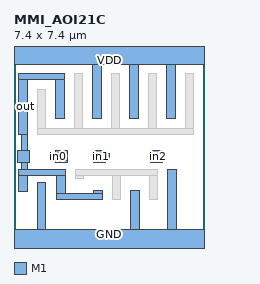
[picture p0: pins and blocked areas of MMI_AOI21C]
MACRO MMI_AOI21C
	CLASS CORE ;
	FOREIGN MMI_AOI21C 0 0 ;
	SIZE 7.4 BY 7.4 ;
	SYMMETRY X Y ;
	SITE CORE1 ;
	PIN out
		DIRECTION output ;
		USE SIGNAL ;
		PORT
			LAYER M1 ;
			RECT 0.18 6.34 1.96 6.57 ;
			LAYER M1 ;
			RECT 0.18 4.195 0.52 6.34 ;
			LAYER M1 ;
			RECT 1.62 4.815 1.96 6.34 ;
			LAYER M1 ;
			RECT 0.29 3.555 0.52 4.195 ;
			LAYER M1 ;
			RECT 0.145 3.105 0.595 3.555 ;
			LAYER M1 ;
			RECT 0.29 2.805 0.52 3.105 ;
			LAYER M1 ;
			RECT 0.18 2.575 2 2.805 ;
			LAYER M1 ;
			RECT 0.18 1.965 0.52 2.575 ;
			LAYER M1 ;
			RECT 1.66 1.89 2 2.575 ;
			LAYER M1 ;
			RECT 3.1 1.89 3.44 2 ;
			LAYER M1 ;
			RECT 1.66 1.66 3.44 1.89 ;
		END
		AntennaDiffArea 4.2872 ;
	END out
	PIN in1
		DIRECTION input ;
		USE SIGNAL ;
		PORT
			LAYER M1 ;
			RECT 3.105 3.5 3.555 3.555 ;
			LAYER M1 ;
			RECT 3.105 3.445 3.64 3.5 ;
			LAYER M1 ;
			RECT 3.105 3.215 3.705 3.445 ;
			LAYER M1 ;
			RECT 3.105 3.16 3.64 3.215 ;
			LAYER M1 ;
			RECT 3.105 3.105 3.555 3.16 ;
		END
		AntennaGateArea 1.9872 ;
	END in1
	PIN GND
		DIRECTION inout ;
		USE GROUND ;
		PORT
			LAYER M1 ;
			RECT 0.9 0.5 1.24 2.305 ;
			LAYER M1 ;
			RECT 4.54 0.5 4.88 2 ;
			LAYER M1 ;
			RECT 5.98 0.5 6.32 2.805 ;
			LAYER M1 ;
			RECT 0 -0.5 7.4 0.5 ;
		END
	END GND
	PIN in2
		DIRECTION input ;
		USE SIGNAL ;
		PORT
			LAYER M1 ;
			RECT 5.325 3.5 5.775 3.555 ;
			LAYER M1 ;
			RECT 5.325 3.445 5.8 3.5 ;
			LAYER M1 ;
			RECT 5.325 3.215 5.865 3.445 ;
			LAYER M1 ;
			RECT 5.325 3.16 5.8 3.215 ;
			LAYER M1 ;
			RECT 5.325 3.105 5.775 3.16 ;
		END
		AntennaGateArea 1.9872 ;
	END in2
	PIN VDD
		DIRECTION inout ;
		USE POWER ;
		PORT
			LAYER M1 ;
			RECT 0 6.9 7.4 7.9 ;
			LAYER M1 ;
			RECT 3.06 4.815 3.4 6.9 ;
			LAYER M1 ;
			RECT 4.5 4.815 4.84 6.9 ;
			LAYER M1 ;
			RECT 5.94 4.815 6.28 6.9 ;
		END
	END VDD
	PIN in0
		DIRECTION input ;
		USE SIGNAL ;
		PORT
			LAYER M1 ;
			RECT 1.625 3.5 2.075 3.555 ;
			LAYER M1 ;
			RECT 1.38 3.16 2.075 3.5 ;
			LAYER M1 ;
			RECT 1.625 3.105 2.075 3.16 ;
		END
		AntennaGateArea 1.6569 ;
	END in0
	OBS
		LAYER M1 ;
		RECT 0.9 4.425 1.24 5.945 ;
		LAYER M1 ;
		RECT 2.34 4.425 2.68 6.57 ;
		LAYER M1 ;
		RECT 3.78 4.425 4.12 6.57 ;
		LAYER M1 ;
		RECT 5.22 4.425 5.56 6.57 ;
		LAYER M1 ;
		RECT 6.66 4.425 7 6.57 ;
		LAYER M1 ;
		RECT 0.9 4.195 7 4.425 ;
		LAYER M1 ;
		RECT 2.38 2.575 5.6 2.805 ;
		LAYER M1 ;
		RECT 2.38 2.46 2.72 2.575 ;
		LAYER M1 ;
		RECT 3.82 1.66 4.16 2.575 ;
		LAYER M1 ;
		RECT 5.26 1.66 5.6 2.575 ;
	END
END MMI_AOI21C
